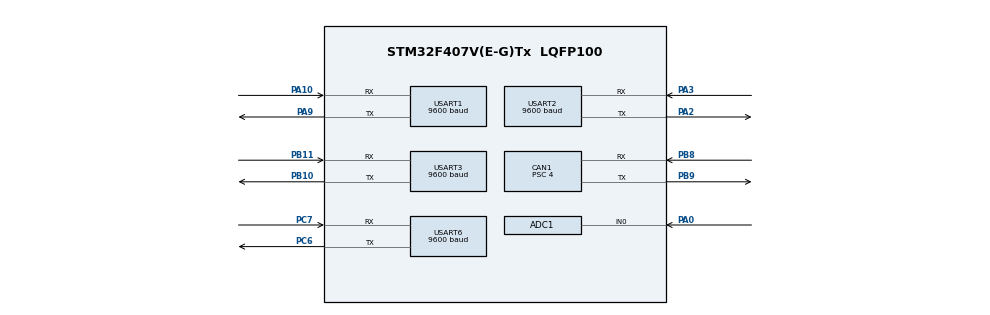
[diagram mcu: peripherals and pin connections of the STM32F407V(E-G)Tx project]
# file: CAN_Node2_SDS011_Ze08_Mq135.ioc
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ADC1.Channel-0\#ChannelRegularConversion=ADC_CHANNEL_0
ADC1.NbrOfConversion=1
ADC1.NbrOfConversionFlag=1
ADC1.Rank-0\#ChannelRegularConversion=1
ADC1.SamplingTime-0\#ChannelRegularConversion=ADC_SAMPLETIME_144CYCLES
ADC1.master=1
CAN1.BS1=CAN_BS1_8TQ
CAN1.CalculateBaudRate=1000000
CAN1.CalculateTimeBit=1000
CAN1.CalculateTimeQuantum=100.0
CAN1.Prescaler=4
Mcu.Family=STM32F4
Mcu.Name=STM32F407V(E-G)Tx
Mcu.Package=LQFP100
NVIC.ADC_IRQn=true\:0\:0\:false\:false\:true\:true\:true\:true
NVIC.PriorityGroup=NVIC_PRIORITYGROUP_0
NVIC.TIM6_DAC_IRQn=true\:0\:0\:false\:false\:true\:true\:true\:true
NVIC.USART1_IRQn=true\:0\:0\:false\:false\:true\:true\:true\:true
NVIC.USART2_IRQn=true\:0\:0\:false\:false\:true\:true\:true\:true
NVIC.USART3_IRQn=true\:0\:0\:false\:false\:true\:true\:true\:true
NVIC.USART6_IRQn=true\:0\:0\:false\:false\:true\:true\:true\:true
PA0-WKUP.Signal=ADCx_IN0
PA10.Mode=Asynchronous
PA10.Signal=USART1_RX
PA2.Mode=Asynchronous
PA2.Signal=USART2_TX
PA3.Mode=Asynchronous
PA3.Signal=USART2_RX
PA9.Mode=Asynchronous
PA9.Signal=USART1_TX
PB10.Mode=Asynchronous
PB10.Signal=USART3_TX
PB11.Mode=Asynchronous
PB11.Signal=USART3_RX
PB8.Mode=CAN_Activate
PB8.Signal=CAN1_RX
PB9.Mode=CAN_Activate
PB9.Signal=CAN1_TX
PC6.Mode=Asynchronous
PC6.Signal=USART6_TX
PC7.Mode=Asynchronous
PC7.Signal=USART6_RX
PH0-OSC_IN.Mode=HSE-External-Oscillator
PH0-OSC_IN.Signal=RCC_OSC_IN
PH1-OSC_OUT.Mode=HSE-External-Oscillator
PH1-OSC_OUT.Signal=RCC_OSC_OUT
ProjectManager.HeapSize=0x200
ProjectManager.StackSize=0x400
ProjectManager.TargetToolchain=EWARM V8.50
RCC.48MHZClocksFreq_Value=45714285.71428572
RCC.AHBFreq_Value=160000000
RCC.APB1CLKDivider=RCC_HCLK_DIV4
RCC.APB1Freq_Value=40000000
RCC.APB1TimFreq_Value=80000000
RCC.APB2CLKDivider=RCC_HCLK_DIV2
RCC.APB2Freq_Value=80000000
RCC.APB2TimFreq_Value=160000000
RCC.CortexFreq_Value=160000000
RCC.HCLKFreq_Value=160000000
RCC.HSE_VALUE=8000000
RCC.HSI_VALUE=16000000
RCC.PLLM=4
RCC.PLLN=160
RCC.PLLQ=7
RCC.PLLSourceVirtual=RCC_PLLSOURCE_HSE
RCC.SYSCLKFreq_VALUE=160000000
RCC.SYSCLKSource=RCC_SYSCLKSOURCE_PLLCLK
RCC.VCOOutputFreq_Value=320000000
SH.ADCx_IN0.0=ADC1_IN0,IN0
TIM6.Period=10000-1
TIM6.Prescaler=8000-1
USART1.BaudRate=9600
USART1.VirtualMode=VM_ASYNC
USART2.BaudRate=9600
USART2.VirtualMode=VM_ASYNC
USART3.BaudRate=9600
USART3.VirtualMode=VM_ASYNC
USART6.BaudRate=9600
USART6.VirtualMode=VM_ASYNC
VP_TIM6_VS_ClockSourceINT.Mode=Enable_Timer
board=STM32F407G-DISC1

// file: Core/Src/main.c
#include "main.h"
#include "sds011.h"
#include <stdio.h>

#define MAXLENGTH 9
typedef enum
{
  ZE_OK,
  ZE_ERROR,
} ZE08_t;
/* USER CODE BEGIN Includes */
uint8_t receivedCommandStack[MAXLENGTH];
uint8_t checkSum(uint8_t array[], uint8_t length);
ZE08_t receivedFlag;
uint8_t serial_available[1];
  float ppm;
  float ppb;
  float ZE08_Value;

CAN_TxHeaderTypeDef TxHeader;
uint32_t TxMailbox;
CAN_RxHeaderTypeDef RxHeader;

ADC_HandleTypeDef hadc1;

CAN_HandleTypeDef hcan1;

TIM_HandleTypeDef htim6;

UART_HandleTypeDef huart1;
UART_HandleTypeDef huart2;
UART_HandleTypeDef huart3;
UART_HandleTypeDef huart6;

/* USER CODE BEGIN PV */
SDS sds;
uint32_t MQ135_value = 0;
uint8_t data[50];
uint16_t size = 0;

uint8_t TxData[8U];
uint8_t TxData1[8U];
uint8_t TxData2[8U];
uint8_t TxData3[8U];
uint8_t RxData[8U];
uint8_t Command_Case1[8U] = "_Default";
uint8_t Command_Case2[8U] = "_Parking";
uint8_t Command_Case3[8U] = "Database";
/* USER CODE END PV */
uint8_t Node_Main_Flag;
uint8_t isTransmit;

void SystemClock_Config(void);
static void MX_GPIO_Init(void);
static void MX_CAN1_Init(void);
static void MX_TIM6_Init(void);
static void MX_USART1_UART_Init(void);
static void MX_USART2_UART_Init(void);
static void MX_USART3_UART_Init(void);
static void MX_USART6_UART_Init(void);
static void MX_ADC1_Init(void);
/* USER CODE BEGIN PFP */
void CAN_Filter_Config(void);
/* USER CODE END PFP */

/* USER CODE BEGIN 0 */
uint8_t checkSum(uint8_t array[], uint8_t length)
{
    uint8_t sum = 0;
    int i;
    for (i = 1; i < length - 1; i ++)
    {
        sum += array[i];
    }
    sum = (~sum) + 1;
    return sum;
}

ZE08_t available1()
{
  uint8_t sumNum ;
  //new data was recevied
  while (__HAL_UART_GET_FLAG(&huart3, UART_FLAG_RXNE) == SET)
  {
//    for (index = 0; index < MAXLENGTH - 1; index++)
//    {
//      receivedCommandStack[index] = receivedCommandStack[index + 1];
//    }
    HAL_UART_Receive(&huart3,receivedCommandStack,MAXLENGTH,1000);

    //receivedCommandStack[MAXLENGTH - 1];

    sumNum = checkSum(receivedCommandStack, MAXLENGTH);
    if ((receivedCommandStack[0] == 0xFF) && (receivedCommandStack[1] == 0x17) && (receivedCommandStack[2] == 0x04) && (receivedCommandStack[MAXLENGTH - 1] == sumNum))
    {
      //head bit and sum are all right
      receivedFlag = ZE_OK; //new data received
      break;
    }
    else
    {
       receivedFlag = ZE_ERROR; //data loss or error
    }
  }
  return receivedFlag;
}

float ze08_PPM()
{
  //HAL_UART_Receive(&huart3,receivedCommandStack,MAXLENGTH,1000);
  if (available1() == ZE_OK)
  {
     receivedFlag = ZE_ERROR;
     ppb = (unsigned int) (receivedCommandStack[4] * 256) + receivedCommandStack[5]; // bit 4: ppm high 8-bit; bit 5: ppm low 8-bit
     ppm = ppb / 1000; // 1ppb = 1000ppm
     HAL_Delay(1000);

  }
  return ppm;
}

uint8_t check_command(uint8_t *command,uint8_t *compare_command)
{
  int i = 0;
  uint8_t retval = 1U;
  while((command[i] == compare_command[i])&& (i < 8U))
  {
    i ++;
  }
  if (i < 7U)
  {
    retval = 0U;
  }
  return retval;
}
/* USER CODE END 0 */

void HAL_CAN_RxFifo0MsgPendingCallback(CAN_HandleTypeDef *hcan)
{
  if (hcan->Instance == hcan1.Instance)
  {
    if (HAL_OK != HAL_CAN_GetRxMessage(hcan,CAN_RX_FIFO0,&RxHeader,RxData))
    {
          Error_Handler();
    }
    else
    {
      HAL_GPIO_TogglePin(GPIOD,GPIO_PIN_12);
      if (RxHeader.StdId == 0x446)
      {
          if (1U == check_command(RxData,Command_Case1))
          {
            HAL_TIM_Base_Start_IT(&htim6);
          }
          else if (1U == check_command(RxData,Command_Case2))
          {
            HAL_TIM_Base_Stop_IT(&htim6);
          }
          else if (1U == check_command(RxData,Command_Case3))
          {
            HAL_TIM_Base_Stop_IT(&htim6);
          }
          else
          {
            /* normally working */
          }
      }
      else
      {

      }
    }
  }
}

uint8_t Flag = 0;

void HAL_TIM_PeriodElapsedCallback(TIM_HandleTypeDef *htim)
{
  if (htim->Instance == htim6.Instance)
  {
      Flag = 1;
  }
}
int main(void)
{

  /* MCU Configuration--------------------------------------------------------*/

  /* Reset of all peripherals, Initializes the Flash interface and the Systick. */
  HAL_Init();

  /* Configure the system clock */
  SystemClock_Config();

  /* Initialize all configured peripherals */
  MX_GPIO_Init();
  MX_CAN1_Init();
  CAN_Filter_Config();
  if (HAL_OK != HAL_CAN_Start(&hcan1))
  {
    Error_Handler();
  }

  if (HAL_OK != HAL_CAN_ActivateNotification(&hcan1,CAN_IT_RX_FIFO0_MSG_PENDING))
  {
    Error_Handler();
  }
      TxHeader.DLC = 8;
    TxHeader.IDE = CAN_ID_STD;
    TxHeader.RTR = CAN_RTR_DATA;
    TxHeader.StdId = 0x659;

  MX_TIM6_Init();

  MX_USART1_UART_Init();
  MX_USART2_UART_Init();
  sdsInit(&sds, &huart1);
  MX_USART3_UART_Init();
  MX_USART6_UART_Init();
  MX_ADC1_Init();
  /* USER CODE BEGIN 2 */
  HAL_TIM_Base_Start_IT(&htim6);
  /* USER CODE END 2 */

  /* Infinite loop */
  while (1)
  {
    if (Flag == 1)
    {
     ZE08_Value = ze08_PPM();

     TxData3[0] = '3';
     TxData3[1] = '.';
     TxData3[2] = '0';
     TxData3[3] = '0';
     TxData3[4] = '0' + (uint8_t)ZE08_Value/ 100;
     TxData3[5] = '0' + ((uint8_t)ZE08_Value % 100)/10;
     TxData3[6] = '0' + (uint8_t)ZE08_Value% 10;
     TxData3[7] = '\n';
     HAL_CAN_AddTxMessage(&hcan1,&TxHeader,TxData3,&TxMailbox);

      size = sprintf((char*)data, "%d %d \n\r", sdsGetPm2_5(&sds), sdsGetPm10(&sds));
      HAL_UART_Transmit_IT(&huart2, data, size);

     //size = sprintf((char*)data, "%d %d \n\r", sdsGetPm2_5(&sds), sdsGetPm10(&sds));
     //HAL_UART_Transmit_IT(&huart2, data, size);
     //HAL_Delay(1000);

     TxData[0] = '4';
     TxData[1] = '.';
     TxData[2] = '0';
     TxData[3] = '0';
     TxData[4] = '0' + (uint8_t)sds.pm_2_5/ 100;
     TxData[5] = '0' + ((uint8_t)sds.pm_2_5 % 100)/10;
     TxData[6] = '0' + (uint8_t)sds.pm_2_5% 10;
     TxData[7] = '\n';

     HAL_CAN_AddTxMessage(&hcan1,&TxHeader,TxData,&TxMailbox);
     //if (HAL_OK != HAL_CAN_AddTxMessage(&hcan1,&TxHeader,TxData,&TxMailbox))
     //{
     //  HAL_GPIO_TogglePin(GPIOD, GPIO_PIN_12|GPIO_PIN_13|GPIO_PIN_14);
     //  Error_Handler();
     //}

     TxData1[0] = '5';
     TxData1[1] = '.';
     TxData1[2] = '0';
     TxData1[3] = '0';
     TxData1[4] = '0' + (uint8_t)sds.pm_10/ 100;
     TxData1[5] = '0' + ((uint8_t)sds.pm_10 % 100)/10;
     TxData1[6] = '0' + (uint8_t)sds.pm_10% 10;
     TxData1[7] = '\n';
     //if (HAL_OK != HAL_CAN_AddTxMessage(&hcan1,&TxHeader,TxData,&TxMailbox))
     //{
     //  Error_Handler();
     //}
     HAL_CAN_AddTxMessage(&hcan1,&TxHeader,TxData1,&TxMailbox);

     HAL_ADC_Start(&hadc1);
     HAL_Delay(1);
     MQ135_value = HAL_ADC_GetValue(&hadc1);
     //HAL_ADC_Stop(&hadc1);
     //HAL_Delay(5);

     TxData2[0] = '6';
     TxData2[1] = '.';
     TxData2[2] = '0' + (uint32_t)MQ135_value/ 10000;
     TxData2[3] = '0'+ ((uint32_t)MQ135_value% 10000)/1000;
     TxData2[4] = '0' + (((uint32_t)MQ135_value% 10000)%1000)/100;
     TxData2[5] = '0' + ((((uint32_t)MQ135_value% 10000)%1000)%100)/10;
     TxData2[6] = '0' + ((((uint32_t)MQ135_value% 10000)%1000)%100)%10;
     TxData2[7] = '\n';

     HAL_CAN_AddTxMessage(&hcan1,&TxHeader,TxData2,&TxMailbox);
     Flag = 0;
    }
      //HAL_Delay(1000);
  }
}

void SystemClock_Config(void)
{
  RCC_OscInitTypeDef RCC_OscInitStruct = {0};
  RCC_ClkInitTypeDef RCC_ClkInitStruct = {0};

  /** Configure the main internal regulator output voltage
  */
  __HAL_RCC_PWR_CLK_ENABLE();
  __HAL_PWR_VOLTAGESCALING_CONFIG(PWR_REGULATOR_VOLTAGE_SCALE1);

  /** Initializes the RCC Oscillators according to the specified parameters
  * in the RCC_OscInitTypeDef structure.
  */
  RCC_OscInitStruct.OscillatorType = RCC_OSCILLATORTYPE_HSI;
  RCC_OscInitStruct.HSIState = RCC_HSI_ON;
  RCC_OscInitStruct.HSICalibrationValue = RCC_HSICALIBRATION_DEFAULT;
  RCC_OscInitStruct.PLL.PLLState = RCC_PLL_ON;
  RCC_OscInitStruct.PLL.PLLSource = RCC_PLLSOURCE_HSI;
  RCC_OscInitStruct.PLL.PLLM = 8;
  RCC_OscInitStruct.PLL.PLLN = 72;
  RCC_OscInitStruct.PLL.PLLP = RCC_PLLP_DIV2;
  RCC_OscInitStruct.PLL.PLLQ = 7;
  if (HAL_RCC_OscConfig(&RCC_OscInitStruct) != HAL_OK)
  {
    Error_Handler();
  }

  /** Initializes the CPU, AHB and APB buses clocks
  */
  RCC_ClkInitStruct.ClockType = RCC_CLOCKTYPE_HCLK|RCC_CLOCKTYPE_SYSCLK
                              |RCC_CLOCKTYPE_PCLK1|RCC_CLOCKTYPE_PCLK2;
  RCC_ClkInitStruct.SYSCLKSource = RCC_SYSCLKSOURCE_PLLCLK;
  RCC_ClkInitStruct.AHBCLKDivider = RCC_SYSCLK_DIV1;
  RCC_ClkInitStruct.APB1CLKDivider = RCC_HCLK_DIV2;
  RCC_ClkInitStruct.APB2CLKDivider = RCC_HCLK_DIV4;

  if (HAL_RCC_ClockConfig(&RCC_ClkInitStruct, FLASH_LATENCY_2) != HAL_OK)
  {
    Error_Handler();
  }
}

static void MX_ADC1_Init(void)
{

  ADC_ChannelConfTypeDef sConfig = {0};

  /** Configure the global features of the ADC (Clock, Resolution, Data Alignment and number of conversion)
  */
  hadc1.Instance = ADC1;
  hadc1.Init.ClockPrescaler = ADC_CLOCK_SYNC_PCLK_DIV4;
  hadc1.Init.Resolution = ADC_RESOLUTION_10B;
  hadc1.Init.ScanConvMode = DISABLE;
  hadc1.Init.ContinuousConvMode = DISABLE;
  hadc1.Init.DiscontinuousConvMode = DISABLE;
  hadc1.Init.ExternalTrigConvEdge = ADC_EXTERNALTRIGCONVEDGE_NONE;
  hadc1.Init.ExternalTrigConv = ADC_SOFTWARE_START;
  hadc1.Init.DataAlign = ADC_DATAALIGN_RIGHT;
  hadc1.Init.NbrOfConversion = 1;
  hadc1.Init.DMAContinuousRequests = DISABLE;
  hadc1.Init.EOCSelection = ADC_EOC_SINGLE_CONV;
  if (HAL_ADC_Init(&hadc1) != HAL_OK)
  {
    Error_Handler();
  }

  /** Configure for the selected ADC regular channel its corresponding rank in the sequencer and its sample time.
  */
  sConfig.Channel = ADC_CHANNEL_0;
  sConfig.Rank = 1;
  sConfig.SamplingTime = ADC_SAMPLETIME_144CYCLES;
  if (HAL_ADC_ConfigChannel(&hadc1, &sConfig) != HAL_OK)
  {
    Error_Handler();
  }

}

static void MX_CAN1_Init(void)
{

  hcan1.Instance = CAN1;
  hcan1.Init.Prescaler = 2;
  hcan1.Init.Mode = CAN_MODE_NORMAL;
  hcan1.Init.SyncJumpWidth = CAN_SJW_1TQ;
  hcan1.Init.TimeSeg1 = CAN_BS1_15TQ;
  hcan1.Init.TimeSeg2 = CAN_BS2_2TQ;
  hcan1.Init.TimeTriggeredMode = DISABLE;
  hcan1.Init.AutoBusOff = ENABLE;
  hcan1.Init.AutoWakeUp = ENABLE;
  hcan1.Init.AutoRetransmission = ENABLE;
  hcan1.Init.ReceiveFifoLocked = DISABLE;
  hcan1.Init.TransmitFifoPriority = DISABLE;
  if (HAL_CAN_Init(&hcan1) != HAL_OK)
  {
    Error_Handler();
  }

}

void HAL_UART_RxCpltCallback(UART_HandleTypeDef *huart)
{
  sds_uart_RxCpltCallback(&sds,huart);
}

void CAN_Filter_Config(void)
{
  CAN_FilterTypeDef can1_filter_init;

  can1_filter_init.FilterActivation = ENABLE;
  can1_filter_init.FilterBank  = 0;
  can1_filter_init.FilterFIFOAssignment = CAN_FILTER_FIFO0;
  can1_filter_init.FilterIdHigh = (0X446)<<5;
  can1_filter_init.FilterIdLow = 0x0000;
  can1_filter_init.FilterMaskIdHigh = (0X651)<<5;
  can1_filter_init.FilterMaskIdLow = 0x0000;
  can1_filter_init.FilterMode = CAN_FILTERMODE_IDLIST;
  can1_filter_init.FilterScale = CAN_FILTERSCALE_32BIT;
  //can1_filter_init.SlaveStartFilterBank = 0; /* doesn't mastter in signel can controller */

  if( HAL_CAN_ConfigFilter(&hcan1,&can1_filter_init) != HAL_OK)
  {
    Error_Handler();
  }
}

static void MX_TIM6_Init(void)
{

  TIM_MasterConfigTypeDef sMasterConfig = {0};

  htim6.Instance = TIM6;
  htim6.Init.Prescaler = 7200-1;
  htim6.Init.CounterMode = TIM_COUNTERMODE_UP;
  htim6.Init.Period = 10000-1;
  htim6.Init.AutoReloadPreload = TIM_AUTORELOAD_PRELOAD_DISABLE;
  if (HAL_TIM_Base_Init(&htim6) != HAL_OK)
  {
    Error_Handler();
  }
  sMasterConfig.MasterOutputTrigger = TIM_TRGO_RESET;
  sMasterConfig.MasterSlaveMode = TIM_MASTERSLAVEMODE_DISABLE;
  if (HAL_TIMEx_MasterConfigSynchronization(&htim6, &sMasterConfig) != HAL_OK)
  {
    Error_Handler();
  }

}

static void MX_USART1_UART_Init(void)
{

  huart1.Instance = USART1;
  huart1.Init.BaudRate = 9600;
  huart1.Init.WordLength = UART_WORDLENGTH_8B;
  huart1.Init.StopBits = UART_STOPBITS_1;
  huart1.Init.Parity = UART_PARITY_NONE;
  huart1.Init.Mode = UART_MODE_TX_RX;
  huart1.Init.HwFlowCtl = UART_HWCONTROL_NONE;
  huart1.Init.OverSampling = UART_OVERSAMPLING_16;
  if (HAL_UART_Init(&huart1) != HAL_OK)
  {
    Error_Handler();
  }

}

static void MX_USART2_UART_Init(void)
{

  huart2.Instance = USART2;
  huart2.Init.BaudRate = 9600;
  huart2.Init.WordLength = UART_WORDLENGTH_8B;
  huart2.Init.StopBits = UART_STOPBITS_1;
  huart2.Init.Parity = UART_PARITY_NONE;
  huart2.Init.Mode = UART_MODE_TX_RX;
  huart2.Init.HwFlowCtl = UART_HWCONTROL_NONE;
  huart2.Init.OverSampling = UART_OVERSAMPLING_16;
  if (HAL_UART_Init(&huart2) != HAL_OK)
  {
    Error_Handler();
  }

}

static void MX_USART3_UART_Init(void)
{

  huart3.Instance = USART3;
  huart3.Init.BaudRate = 9600;
  huart3.Init.WordLength = UART_WORDLENGTH_8B;
  huart3.Init.StopBits = UART_STOPBITS_1;
  huart3.Init.Parity = UART_PARITY_NONE;
  huart3.Init.Mode = UART_MODE_TX_RX;
  huart3.Init.HwFlowCtl = UART_HWCONTROL_NONE;
  huart3.Init.OverSampling = UART_OVERSAMPLING_16;
  if (HAL_UART_Init(&huart3) != HAL_OK)
  {
    Error_Handler();
  }

}

static void MX_USART6_UART_Init(void)
{

  huart6.Instance = USART6;
  huart6.Init.BaudRate = 9600;
  huart6.Init.WordLength = UART_WORDLENGTH_8B;
  huart6.Init.StopBits = UART_STOPBITS_1;
  huart6.Init.Parity = UART_PARITY_NONE;
  huart6.Init.Mode = UART_MODE_TX_RX;
  huart6.Init.HwFlowCtl = UART_HWCONTROL_NONE;
  huart6.Init.OverSampling = UART_OVERSAMPLING_16;
  if (HAL_UART_Init(&huart6) != HAL_OK)
  {
    Error_Handler();
  }

}

static void MX_GPIO_Init(void)
{
  GPIO_InitTypeDef GPIO_InitStruct = {0};
  /* GPIO Ports Clock Enable */
  __HAL_RCC_GPIOH_CLK_ENABLE();
  __HAL_RCC_GPIOA_CLK_ENABLE();
  __HAL_RCC_GPIOB_CLK_ENABLE();
  __HAL_RCC_GPIOC_CLK_ENABLE();
  __HAL_RCC_GPIOD_CLK_ENABLE();

  /*Configure GPIO pin Output Level */
  HAL_GPIO_WritePin(GPIOD, GPIO_PIN_12|GPIO_PIN_13|GPIO_PIN_14, GPIO_PIN_SET);

  GPIO_InitStruct.Pin = GPIO_PIN_12|GPIO_PIN_13|GPIO_PIN_14;
  GPIO_InitStruct.Mode = GPIO_MODE_OUTPUT_PP;
  GPIO_InitStruct.Pull = GPIO_NOPULL;
  GPIO_InitStruct.Speed = GPIO_SPEED_FREQ_LOW;
  HAL_GPIO_Init(GPIOD, &GPIO_InitStruct);
}

void Error_Handler(void)
{
  __disable_irq();
  while (1)
  {
  }
}
